VERSION 5.7 ;
  NOWIREEXTENSIONATPIN ON ;
  DIVIDERCHAR "/" ;
  BUSBITCHARS "[]" ;
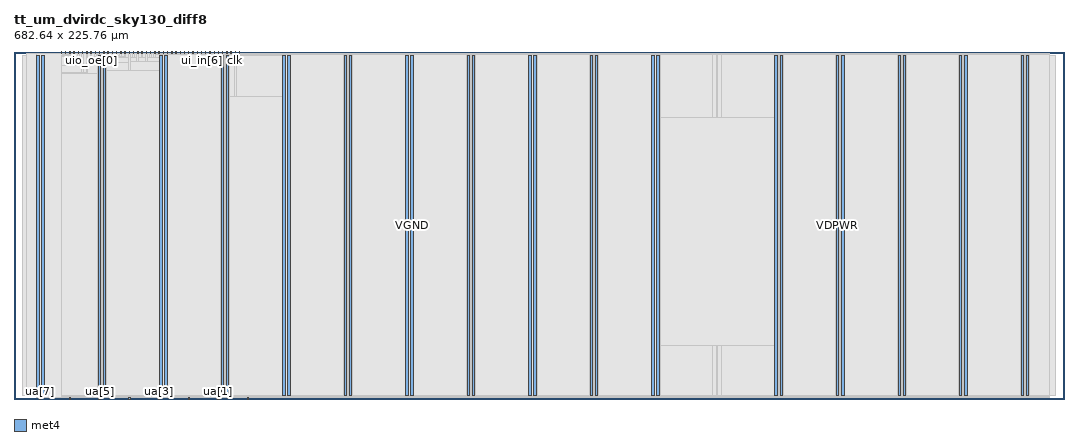
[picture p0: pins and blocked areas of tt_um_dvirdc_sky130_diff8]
MACRO tt_um_dvirdc_sky130_diff8
  CLASS BLOCK ;
  FOREIGN tt_um_dvirdc_sky130_diff8 ;
  ORIGIN 0.000 0.000 ;
  SIZE 682.640 BY 225.760 ;
  PIN VDPWR
    DIRECTION INOUT ;
    USE POWER ;
    PORT
      LAYER met4 ;
        RECT 14.720 2.480 16.320 223.280 ;
    END
    PORT
      LAYER met4 ;
        RECT 54.720 2.480 56.320 223.280 ;
    END
    PORT
      LAYER met4 ;
        RECT 94.720 2.480 96.320 223.280 ;
    END
    PORT
      LAYER met4 ;
        RECT 134.720 2.480 136.320 223.280 ;
    END
    PORT
      LAYER met4 ;
        RECT 174.720 2.480 176.320 223.280 ;
    END
    PORT
      LAYER met4 ;
        RECT 214.720 2.480 216.320 223.280 ;
    END
    PORT
      LAYER met4 ;
        RECT 254.720 2.480 256.320 223.280 ;
    END
    PORT
      LAYER met4 ;
        RECT 294.720 2.480 296.320 223.280 ;
    END
    PORT
      LAYER met4 ;
        RECT 334.720 2.480 336.320 223.280 ;
    END
    PORT
      LAYER met4 ;
        RECT 374.720 2.480 376.320 223.280 ;
    END
    PORT
      LAYER met4 ;
        RECT 414.720 2.480 416.320 223.280 ;
    END
    PORT
      LAYER met4 ;
        RECT 494.720 2.480 496.320 223.280 ;
    END
    PORT
      LAYER met4 ;
        RECT 534.720 2.480 536.320 223.280 ;
    END
    PORT
      LAYER met4 ;
        RECT 574.720 2.480 576.320 223.280 ;
    END
    PORT
      LAYER met4 ;
        RECT 614.720 2.480 616.320 223.280 ;
    END
    PORT
      LAYER met4 ;
        RECT 654.720 2.480 656.320 223.280 ;
    END
  END VDPWR
  PIN VGND
    DIRECTION INOUT ;
    USE GROUND ;
    PORT
      LAYER met4 ;
        RECT 18.020 2.480 19.620 223.280 ;
    END
    PORT
      LAYER met4 ;
        RECT 58.020 2.480 59.620 223.280 ;
    END
    PORT
      LAYER met4 ;
        RECT 98.020 2.480 99.620 223.280 ;
    END
    PORT
      LAYER met4 ;
        RECT 138.020 2.480 139.620 223.280 ;
    END
    PORT
      LAYER met4 ;
        RECT 178.020 2.480 179.620 223.280 ;
    END
    PORT
      LAYER met4 ;
        RECT 218.020 2.480 219.620 223.280 ;
    END
    PORT
      LAYER met4 ;
        RECT 258.020 2.480 259.620 223.280 ;
    END
    PORT
      LAYER met4 ;
        RECT 298.020 2.480 299.620 223.280 ;
    END
    PORT
      LAYER met4 ;
        RECT 338.020 2.480 339.620 223.280 ;
    END
    PORT
      LAYER met4 ;
        RECT 378.020 2.480 379.620 223.280 ;
    END
    PORT
      LAYER met4 ;
        RECT 418.020 2.480 419.620 223.280 ;
    END
    PORT
      LAYER met4 ;
        RECT 498.020 2.480 499.620 223.280 ;
    END
    PORT
      LAYER met4 ;
        RECT 538.020 2.480 539.620 223.280 ;
    END
    PORT
      LAYER met4 ;
        RECT 578.020 2.480 579.620 223.280 ;
    END
    PORT
      LAYER met4 ;
        RECT 618.020 2.480 619.620 223.280 ;
    END
    PORT
      LAYER met4 ;
        RECT 658.020 2.480 659.620 223.280 ;
    END
  END VGND
  PIN clk
    DIRECTION INPUT ;
    USE SIGNAL ;
    PORT
      LAYER met4 ;
        RECT 143.830 224.760 144.130 225.760 ;
    END
  END clk
  PIN ena
    DIRECTION INPUT ;
    USE SIGNAL ;
    PORT
      LAYER met4 ;
        RECT 146.590 224.760 146.890 225.760 ;
    END
  END ena
  PIN rst_n
    DIRECTION INPUT ;
    USE SIGNAL ;
    PORT
      LAYER met4 ;
        RECT 141.070 224.760 141.370 225.760 ;
    END
  END rst_n
  PIN ua[0]
    DIRECTION INOUT ;
    USE SIGNAL ;
    PORT
      LAYER met4 ;
        RECT 151.810 0.000 152.710 1.000 ;
    END
  END ua[0]
  PIN ua[1]
    DIRECTION INOUT ;
    USE SIGNAL ;
    PORT
      LAYER met4 ;
        RECT 132.490 0.000 133.390 1.000 ;
    END
  END ua[1]
  PIN ua[2]
    DIRECTION INOUT ;
    USE SIGNAL ;
    PORT
      LAYER met4 ;
        RECT 113.170 0.000 114.070 1.000 ;
    END
  END ua[2]
  PIN ua[3]
    DIRECTION INOUT ;
    USE SIGNAL ;
    PORT
      LAYER met4 ;
        RECT 93.850 0.000 94.750 1.000 ;
    END
  END ua[3]
  PIN ua[4]
    DIRECTION INOUT ;
    USE SIGNAL ;
    PORT
      LAYER met4 ;
        RECT 74.530 0.000 75.430 1.000 ;
    END
  END ua[4]
  PIN ua[5]
    DIRECTION INOUT ;
    USE SIGNAL ;
    PORT
      LAYER met4 ;
        RECT 55.210 0.000 56.110 1.000 ;
    END
  END ua[5]
  PIN ua[6]
    DIRECTION INOUT ;
    USE SIGNAL ;
    PORT
      LAYER met4 ;
        RECT 35.890 0.000 36.790 1.000 ;
    END
  END ua[6]
  PIN ua[7]
    DIRECTION INOUT ;
    USE SIGNAL ;
    PORT
      LAYER met4 ;
        RECT 16.570 0.000 17.470 1.000 ;
    END
  END ua[7]
  PIN ui_in[0]
    DIRECTION INPUT ;
    USE SIGNAL ;
    PORT
      LAYER met4 ;
        RECT 138.310 224.760 138.610 225.760 ;
    END
  END ui_in[0]
  PIN ui_in[1]
    DIRECTION INPUT ;
    USE SIGNAL ;
    PORT
      LAYER met4 ;
        RECT 135.550 224.760 135.850 225.760 ;
    END
  END ui_in[1]
  PIN ui_in[2]
    DIRECTION INPUT ;
    USE SIGNAL ;
    PORT
      LAYER met4 ;
        RECT 132.790 224.760 133.090 225.760 ;
    END
  END ui_in[2]
  PIN ui_in[3]
    DIRECTION INPUT ;
    USE SIGNAL ;
    PORT
      LAYER met4 ;
        RECT 130.030 224.760 130.330 225.760 ;
    END
  END ui_in[3]
  PIN ui_in[4]
    DIRECTION INPUT ;
    USE SIGNAL ;
    PORT
      LAYER met4 ;
        RECT 127.270 224.760 127.570 225.760 ;
    END
  END ui_in[4]
  PIN ui_in[5]
    DIRECTION INPUT ;
    USE SIGNAL ;
    PORT
      LAYER met4 ;
        RECT 124.510 224.760 124.810 225.760 ;
    END
  END ui_in[5]
  PIN ui_in[6]
    DIRECTION INPUT ;
    USE SIGNAL ;
    PORT
      LAYER met4 ;
        RECT 121.750 224.760 122.050 225.760 ;
    END
  END ui_in[6]
  PIN ui_in[7]
    DIRECTION INPUT ;
    USE SIGNAL ;
    PORT
      LAYER met4 ;
        RECT 118.990 224.760 119.290 225.760 ;
    END
  END ui_in[7]
  PIN uio_in[0]
    DIRECTION INPUT ;
    USE SIGNAL ;
    PORT
      LAYER met4 ;
        RECT 116.230 224.760 116.530 225.760 ;
    END
  END uio_in[0]
  PIN uio_in[1]
    DIRECTION INPUT ;
    USE SIGNAL ;
    PORT
      LAYER met4 ;
        RECT 113.470 224.760 113.770 225.760 ;
    END
  END uio_in[1]
  PIN uio_in[2]
    DIRECTION INPUT ;
    USE SIGNAL ;
    PORT
      LAYER met4 ;
        RECT 110.710 224.760 111.010 225.760 ;
    END
  END uio_in[2]
  PIN uio_in[3]
    DIRECTION INPUT ;
    USE SIGNAL ;
    PORT
      LAYER met4 ;
        RECT 107.950 224.760 108.250 225.760 ;
    END
  END uio_in[3]
  PIN uio_in[4]
    DIRECTION INPUT ;
    USE SIGNAL ;
    PORT
      LAYER met4 ;
        RECT 105.190 224.760 105.490 225.760 ;
    END
  END uio_in[4]
  PIN uio_in[5]
    DIRECTION INPUT ;
    USE SIGNAL ;
    PORT
      LAYER met4 ;
        RECT 102.430 224.760 102.730 225.760 ;
    END
  END uio_in[5]
  PIN uio_in[6]
    DIRECTION INPUT ;
    USE SIGNAL ;
    PORT
      LAYER met4 ;
        RECT 99.670 224.760 99.970 225.760 ;
    END
  END uio_in[6]
  PIN uio_in[7]
    DIRECTION INPUT ;
    USE SIGNAL ;
    PORT
      LAYER met4 ;
        RECT 96.910 224.760 97.210 225.760 ;
    END
  END uio_in[7]
  PIN uio_oe[0]
    DIRECTION OUTPUT ;
    USE SIGNAL ;
    PORT
      LAYER met4 ;
        RECT 49.990 224.760 50.290 225.760 ;
    END
  END uio_oe[0]
  PIN uio_oe[1]
    DIRECTION OUTPUT ;
    USE SIGNAL ;
    PORT
      LAYER met4 ;
        RECT 47.230 224.760 47.530 225.760 ;
    END
  END uio_oe[1]
  PIN uio_oe[2]
    DIRECTION OUTPUT ;
    USE SIGNAL ;
    PORT
      LAYER met4 ;
        RECT 44.470 224.760 44.770 225.760 ;
    END
  END uio_oe[2]
  PIN uio_oe[3]
    DIRECTION OUTPUT ;
    USE SIGNAL ;
    PORT
      LAYER met4 ;
        RECT 41.710 224.760 42.010 225.760 ;
    END
  END uio_oe[3]
  PIN uio_oe[4]
    DIRECTION OUTPUT ;
    USE SIGNAL ;
    PORT
      LAYER met4 ;
        RECT 38.950 224.760 39.250 225.760 ;
    END
  END uio_oe[4]
  PIN uio_oe[5]
    DIRECTION OUTPUT ;
    USE SIGNAL ;
    PORT
      LAYER met4 ;
        RECT 36.190 224.760 36.490 225.760 ;
    END
  END uio_oe[5]
  PIN uio_oe[6]
    DIRECTION OUTPUT ;
    USE SIGNAL ;
    PORT
      LAYER met4 ;
        RECT 33.430 224.760 33.730 225.760 ;
    END
  END uio_oe[6]
  PIN uio_oe[7]
    DIRECTION OUTPUT ;
    USE SIGNAL ;
    PORT
      LAYER met4 ;
        RECT 30.670 224.760 30.970 225.760 ;
    END
  END uio_oe[7]
  PIN uio_out[0]
    DIRECTION OUTPUT ;
    USE SIGNAL ;
    PORT
      LAYER met4 ;
        RECT 72.070 224.760 72.370 225.760 ;
    END
  END uio_out[0]
  PIN uio_out[1]
    DIRECTION OUTPUT ;
    USE SIGNAL ;
    PORT
      LAYER met4 ;
        RECT 69.310 224.760 69.610 225.760 ;
    END
  END uio_out[1]
  PIN uio_out[2]
    DIRECTION OUTPUT ;
    USE SIGNAL ;
    PORT
      LAYER met4 ;
        RECT 66.550 224.760 66.850 225.760 ;
    END
  END uio_out[2]
  PIN uio_out[3]
    DIRECTION OUTPUT ;
    USE SIGNAL ;
    PORT
      LAYER met4 ;
        RECT 63.790 224.760 64.090 225.760 ;
    END
  END uio_out[3]
  PIN uio_out[4]
    DIRECTION OUTPUT ;
    USE SIGNAL ;
    PORT
      LAYER met4 ;
        RECT 61.030 224.760 61.330 225.760 ;
    END
  END uio_out[4]
  PIN uio_out[5]
    DIRECTION OUTPUT ;
    USE SIGNAL ;
    PORT
      LAYER met4 ;
        RECT 58.270 224.760 58.570 225.760 ;
    END
  END uio_out[5]
  PIN uio_out[6]
    DIRECTION OUTPUT ;
    USE SIGNAL ;
    PORT
      LAYER met4 ;
        RECT 55.510 224.760 55.810 225.760 ;
    END
  END uio_out[6]
  PIN uio_out[7]
    DIRECTION OUTPUT ;
    USE SIGNAL ;
    PORT
      LAYER met4 ;
        RECT 52.750 224.760 53.050 225.760 ;
    END
  END uio_out[7]
  PIN uo_out[0]
    DIRECTION OUTPUT ;
    USE SIGNAL ;
    PORT
      LAYER met4 ;
        RECT 94.150 224.760 94.450 225.760 ;
    END
  END uo_out[0]
  PIN uo_out[1]
    DIRECTION OUTPUT ;
    USE SIGNAL ;
    PORT
      LAYER met4 ;
        RECT 91.390 224.760 91.690 225.760 ;
    END
  END uo_out[1]
  PIN uo_out[2]
    DIRECTION OUTPUT ;
    USE SIGNAL ;
    PORT
      LAYER met4 ;
        RECT 88.630 224.760 88.930 225.760 ;
    END
  END uo_out[2]
  PIN uo_out[3]
    DIRECTION OUTPUT ;
    USE SIGNAL ;
    PORT
      LAYER met4 ;
        RECT 85.870 224.760 86.170 225.760 ;
    END
  END uo_out[3]
  PIN uo_out[4]
    DIRECTION OUTPUT ;
    USE SIGNAL ;
    PORT
      LAYER met4 ;
        RECT 83.110 224.760 83.410 225.760 ;
    END
  END uo_out[4]
  PIN uo_out[5]
    DIRECTION OUTPUT ;
    USE SIGNAL ;
    PORT
      LAYER met4 ;
        RECT 80.350 224.760 80.650 225.760 ;
    END
  END uo_out[5]
  PIN uo_out[6]
    DIRECTION OUTPUT ;
    USE SIGNAL ;
    PORT
      LAYER met4 ;
        RECT 77.590 224.760 77.890 225.760 ;
    END
  END uo_out[6]
  PIN uo_out[7]
    DIRECTION OUTPUT ;
    USE SIGNAL ;
    PORT
      LAYER met4 ;
        RECT 74.830 224.760 75.130 225.760 ;
    END
  END uo_out[7]
  OBS
      LAYER nwell ;
        RECT 5.330 2.635 677.310 223.230 ;
      LAYER li1 ;
        RECT 5.520 2.635 677.120 223.125 ;
      LAYER met1 ;
        RECT 5.520 2.480 677.120 223.280 ;
      LAYER met2 ;
        RECT 8.380 2.535 671.970 224.925 ;
      LAYER met3 ;
        RECT 14.730 0.860 673.170 224.905 ;
      LAYER met4 ;
        RECT 31.370 223.820 33.030 224.905 ;
        RECT 34.130 223.820 35.790 224.905 ;
        RECT 31.370 223.140 35.790 223.820 ;
        RECT 30.655 222.460 35.790 223.140 ;
        RECT 36.890 224.360 38.550 224.905 ;
        RECT 39.650 224.360 41.310 224.905 ;
        RECT 36.890 222.460 41.310 224.360 ;
        RECT 30.655 217.020 41.310 222.460 ;
        RECT 42.410 217.020 44.070 224.905 ;
        RECT 30.655 212.260 44.070 217.020 ;
        RECT 45.170 212.260 46.830 224.905 ;
        RECT 30.655 211.580 46.830 212.260 ;
        RECT 47.930 221.780 49.590 224.905 ;
        RECT 50.690 222.460 52.350 224.905 ;
        RECT 53.450 223.820 55.110 224.905 ;
        RECT 56.210 224.360 57.870 224.905 ;
        RECT 58.970 224.360 60.630 224.905 ;
        RECT 56.210 223.820 60.630 224.360 ;
        RECT 53.450 223.680 60.630 223.820 ;
        RECT 53.450 222.460 54.320 223.680 ;
        RECT 50.690 221.780 54.320 222.460 ;
        RECT 47.930 211.580 54.320 221.780 ;
        RECT 30.655 2.080 54.320 211.580 ;
        RECT 56.720 2.080 57.620 223.680 ;
        RECT 60.020 221.780 60.630 223.680 ;
        RECT 61.730 221.780 63.390 224.905 ;
        RECT 60.020 219.060 63.390 221.780 ;
        RECT 64.490 223.140 66.150 224.905 ;
        RECT 67.250 223.140 68.910 224.905 ;
        RECT 64.490 222.460 68.910 223.140 ;
        RECT 70.010 222.460 71.670 224.905 ;
        RECT 64.490 221.780 71.670 222.460 ;
        RECT 72.770 221.780 74.430 224.905 ;
        RECT 64.490 219.060 74.430 221.780 ;
        RECT 60.020 213.620 74.430 219.060 ;
        RECT 75.530 221.780 77.190 224.905 ;
        RECT 78.290 221.780 79.950 224.905 ;
        RECT 75.530 219.740 79.950 221.780 ;
        RECT 81.050 221.780 82.710 224.905 ;
        RECT 83.810 221.780 85.470 224.905 ;
        RECT 81.050 219.740 85.470 221.780 ;
        RECT 86.570 221.780 88.230 224.905 ;
        RECT 89.330 221.780 90.990 224.905 ;
        RECT 92.090 223.820 93.750 224.905 ;
        RECT 94.850 224.360 96.510 224.905 ;
        RECT 97.610 224.360 99.270 224.905 ;
        RECT 100.370 224.360 102.030 224.905 ;
        RECT 103.130 224.360 104.790 224.905 ;
        RECT 105.890 224.360 107.550 224.905 ;
        RECT 108.650 224.360 110.310 224.905 ;
        RECT 111.410 224.360 113.070 224.905 ;
        RECT 114.170 224.360 115.830 224.905 ;
        RECT 116.930 224.360 118.590 224.905 ;
        RECT 119.690 224.360 121.350 224.905 ;
        RECT 122.450 224.360 124.110 224.905 ;
        RECT 125.210 224.360 126.870 224.905 ;
        RECT 127.970 224.360 129.630 224.905 ;
        RECT 130.730 224.360 132.390 224.905 ;
        RECT 94.850 223.820 132.390 224.360 ;
        RECT 133.490 223.820 135.150 224.905 ;
        RECT 136.250 223.820 137.910 224.905 ;
        RECT 139.010 224.360 140.670 224.905 ;
        RECT 141.770 224.360 143.430 224.905 ;
        RECT 139.010 223.820 143.430 224.360 ;
        RECT 92.090 223.680 143.430 223.820 ;
        RECT 92.090 221.780 94.320 223.680 ;
        RECT 86.570 219.740 94.320 221.780 ;
        RECT 75.530 213.620 94.320 219.740 ;
        RECT 60.020 2.080 94.320 213.620 ;
        RECT 96.720 2.080 97.620 223.680 ;
        RECT 100.020 2.080 134.320 223.680 ;
        RECT 136.720 2.080 137.620 223.680 ;
        RECT 140.020 196.620 143.430 223.680 ;
        RECT 144.530 223.140 146.190 224.905 ;
        RECT 147.290 223.680 673.145 224.905 ;
        RECT 147.290 223.140 174.320 223.680 ;
        RECT 144.530 196.620 174.320 223.140 ;
        RECT 140.020 2.080 174.320 196.620 ;
        RECT 176.720 2.080 177.620 223.680 ;
        RECT 180.020 2.080 214.320 223.680 ;
        RECT 216.720 2.080 217.620 223.680 ;
        RECT 220.020 2.080 254.320 223.680 ;
        RECT 256.720 2.080 257.620 223.680 ;
        RECT 260.020 2.080 294.320 223.680 ;
        RECT 296.720 2.080 297.620 223.680 ;
        RECT 300.020 2.080 334.320 223.680 ;
        RECT 336.720 2.080 337.620 223.680 ;
        RECT 340.020 2.080 374.320 223.680 ;
        RECT 376.720 2.080 377.620 223.680 ;
        RECT 380.020 2.080 414.320 223.680 ;
        RECT 416.720 2.080 417.620 223.680 ;
        RECT 420.020 182.700 454.320 223.680 ;
        RECT 456.720 182.700 457.620 223.680 ;
        RECT 460.020 182.700 494.320 223.680 ;
        RECT 420.020 34.700 494.320 182.700 ;
        RECT 420.020 2.080 454.320 34.700 ;
        RECT 456.720 2.080 457.620 34.700 ;
        RECT 460.020 2.080 494.320 34.700 ;
        RECT 496.720 2.080 497.620 223.680 ;
        RECT 500.020 2.080 534.320 223.680 ;
        RECT 536.720 2.080 537.620 223.680 ;
        RECT 540.020 2.080 574.320 223.680 ;
        RECT 576.720 2.080 577.620 223.680 ;
        RECT 580.020 2.080 614.320 223.680 ;
        RECT 616.720 2.080 617.620 223.680 ;
        RECT 620.020 2.080 654.320 223.680 ;
        RECT 656.720 2.080 657.620 223.680 ;
        RECT 660.020 2.080 673.145 223.680 ;
        RECT 30.655 1.400 673.145 2.080 ;
        RECT 30.655 0.855 35.490 1.400 ;
        RECT 37.190 0.855 54.810 1.400 ;
        RECT 56.510 0.855 74.130 1.400 ;
        RECT 75.830 0.855 93.450 1.400 ;
        RECT 95.150 0.855 112.770 1.400 ;
        RECT 114.470 0.855 132.090 1.400 ;
        RECT 133.790 0.855 151.410 1.400 ;
        RECT 153.110 0.855 673.145 1.400 ;
  END
END tt_um_dvirdc_sky130_diff8
END LIBRARY

